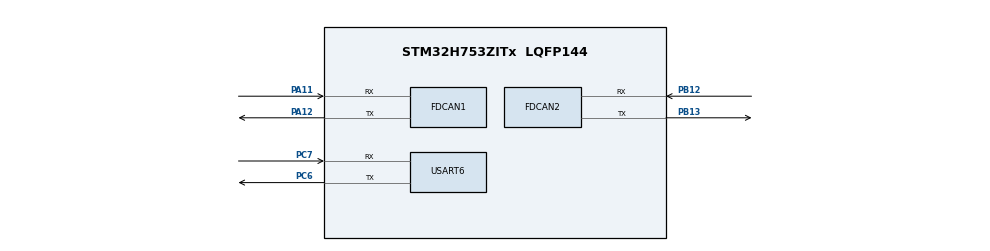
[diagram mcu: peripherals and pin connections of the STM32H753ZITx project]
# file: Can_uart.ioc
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CORTEX_M7.CPU_DCache=Disabled
CORTEX_M7.CPU_ICache=Disabled
CORTEX_M7.MPU_Control=__NULL
CORTEX_M7.default_mode_Activation=1
FDCAN1.CalculateBaudRateNominal=937499
FDCAN1.CalculateTimeBitNominal=1066
FDCAN1.CalculateTimeQuantumNominal=66.66666666666667
FDCAN1.Mode=FDCAN_MODE_INTERNAL_LOOPBACK
FDCAN1.NominalPrescaler=5
FDCAN1.NominalTimeSeg1=13
FDCAN1.NominalTimeSeg2=2
FDCAN1.RxFifo0ElmtsNbr=8
FDCAN1.StdFiltersNbr=64
FDCAN1.TxBuffersNbr=32
FDCAN2.CalculateBaudRateNominal=937499
FDCAN2.CalculateTimeBitNominal=1066
FDCAN2.CalculateTimeQuantumNominal=66.66666666666667
FDCAN2.Mode=FDCAN_MODE_INTERNAL_LOOPBACK
FDCAN2.NominalPrescaler=5
FDCAN2.NominalTimeSeg1=13
FDCAN2.NominalTimeSeg2=2
FDCAN2.RxFifo0ElmtsNbr=8
FDCAN2.StdFiltersNbr=64
FDCAN2.TxBuffersNbr=32
Mcu.Family=STM32H7
Mcu.Name=STM32H753ZITx
Mcu.Package=LQFP144
NVIC.FDCAN1_IT0_IRQn=true\:0\:0\:false\:false\:true\:true\:true\:true
NVIC.FDCAN2_IT0_IRQn=true\:0\:0\:false\:false\:true\:true\:true\:true
NVIC.PriorityGroup=NVIC_PRIORITYGROUP_4
PA11.Mode=FDCAN_Activate
PA11.Signal=FDCAN1_RX
PA12.Mode=FDCAN_Activate
PA12.Signal=FDCAN1_TX
PB0.TagName=LD1
PB12.Mode=FDCAN_Activate
PB12.Signal=FDCAN2_RX
PB13.Mode=FDCAN_Activate
PB13.Signal=FDCAN2_TX
PB14.TagName=LD3
PB7.TagName=LD2
PC13.TagName=BUTTON
PC6.Mode=Asynchronous
PC6.Signal=USART6_TX
PC7.Mode=Asynchronous
PC7.Signal=USART6_RX
PD8.TagName=VCP_TX
PD9.TagName=VCP_RX
ProjectManager.HeapSize=0x200
ProjectManager.StackSize=0x400
ProjectManager.TargetToolchain=STM32CubeIDE
RCC.ADCFreq_Value=129000000
RCC.APB1Freq_Value=64000000
RCC.APB2Freq_Value=64000000
RCC.APB3Freq_Value=64000000
RCC.APB4Freq_Value=64000000
RCC.CortexFreq_Value=64000000
RCC.DIVM1=4
RCC.DIVN1=9
RCC.HCLKFreq_Value=64000000
RCC.HSE_VALUE=8000000
RCC.PLLFRACN=3072
RCC.PWR_Regulator_Voltage_Scale=PWR_REGULATOR_VOLTAGE_SCALE2
RCC.SYSCLKFreq_VALUE=64000000
RCC.USBFreq_Value=75000000
USART6.VirtualMode-Asynchronous=VM_ASYNC
VP_MEMORYMAP_VS_MEMORYMAP.Mode=CurAppReg
board=NUCLEO-H753ZI

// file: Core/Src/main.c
/* USER CODE BEGIN Header */
/**
  ******************************************************************************
  * @file           : main.c
  * @brief          : Main program body
  ******************************************************************************
  * @attention
  *
  * Copyright (c) 2026 STMicroelectronics.
  * All rights reserved.
  *
  * This software is licensed under terms that can be found in the LICENSE file
  * in the root directory of this software component.
  * If no LICENSE file comes with this software, it is provided AS-IS.
  *
  ******************************************************************************
  */
/* USER CODE END Header */

#include "main.h"
#include <stdio.h>
#include <string.h>

FDCAN_HandleTypeDef hfdcan1;
FDCAN_HandleTypeDef hfdcan2;

UART_HandleTypeDef huart6;

/* USER CODE BEGIN PV */
FDCAN_RxHeaderTypeDef RxHeader1;
FDCAN_RxHeaderTypeDef RxHeader2;

uint8_t RxData1[8];
uint8_t RxData2[8];

FDCAN_TxHeaderTypeDef TxHeader;
uint8_t TxData[8];
/* USER CODE END PV */

void SystemClock_Config(void);
static void MX_GPIO_Init(void);
static void MX_FDCAN1_Init(void);
static void MX_FDCAN2_Init(void);
static void MX_USART6_UART_Init(void);

/* USER CODE BEGIN PFP */
void FDCAN_Filter_Config(void);
void FDCAN_Start_All(void);
void Send_CAN(FDCAN_HandleTypeDef *hfdcan, uint32_t id, uint8_t val);
/* USER CODE END PFP */

/* USER CODE BEGIN 0 */

/* printf redirection to UART */
int _write(int file, char *ptr, int len)
{
  HAL_UART_Transmit(&huart6, (uint8_t *)ptr, len, HAL_MAX_DELAY);
  return len;
}

/* Configure Filters + Global Filters */
void FDCAN_Filter_Config(void)
{
  FDCAN_FilterTypeDef sFilter;

  /* ------------ FDCAN1 filter ------------ */
  sFilter.IdType       = FDCAN_STANDARD_ID;
  sFilter.FilterIndex  = 0;
  sFilter.FilterType   = FDCAN_FILTER_MASK;
  sFilter.FilterConfig = FDCAN_FILTER_TO_RXFIFO0;
  sFilter.FilterID1    = 0x111;
  sFilter.FilterID2    = 0x7FF;

  if (HAL_FDCAN_ConfigFilter(&hfdcan1, &sFilter) != HAL_OK)
  {
    Error_Handler();
  }

  /* ------------ FDCAN2 filter ------------ */
  sFilter.FilterIndex  = 0;
  sFilter.FilterID1    = 0x222;

  if (HAL_FDCAN_ConfigFilter(&hfdcan2, &sFilter) != HAL_OK)
  {
    Error_Handler();
  }

  /* Global filter: accept all standard IDs that don't match filters */
  if (HAL_FDCAN_ConfigGlobalFilter(&hfdcan1,
                                  FDCAN_ACCEPT_IN_RX_FIFO0,
                                  FDCAN_ACCEPT_IN_RX_FIFO0,
                                  DISABLE,
                                  DISABLE) != HAL_OK)
  {
    Error_Handler();
  }

  if (HAL_FDCAN_ConfigGlobalFilter(&hfdcan2,
                                  FDCAN_ACCEPT_IN_RX_FIFO0,
                                  FDCAN_ACCEPT_IN_RX_FIFO0,
                                  DISABLE,
                                  DISABLE) != HAL_OK)
  {
    Error_Handler();
  }
}

void FDCAN_Start_All(void)
{
  if (HAL_FDCAN_Start(&hfdcan1) != HAL_OK)
  {
    Error_Handler();
  }

  if (HAL_FDCAN_Start(&hfdcan2) != HAL_OK)
  {
    Error_Handler();
  }

  if (HAL_FDCAN_ActivateNotification(&hfdcan1, FDCAN_IT_RX_FIFO0_NEW_MESSAGE, 0) != HAL_OK)
  {
    Error_Handler();
  }

  if (HAL_FDCAN_ActivateNotification(&hfdcan2, FDCAN_IT_RX_FIFO0_NEW_MESSAGE, 0) != HAL_OK)
  {
    Error_Handler();
  }
}

void Send_CAN(FDCAN_HandleTypeDef *hfdcan, uint32_t id, uint8_t val)
{
  TxHeader.Identifier          = id;
  TxHeader.IdType              = FDCAN_STANDARD_ID;
  TxHeader.TxFrameType         = FDCAN_DATA_FRAME;
  TxHeader.DataLength          = FDCAN_DLC_BYTES_1;
  TxHeader.ErrorStateIndicator = FDCAN_ESI_ACTIVE;
  TxHeader.BitRateSwitch       = FDCAN_BRS_OFF;
  TxHeader.FDFormat            = FDCAN_CLASSIC_CAN;
  TxHeader.TxEventFifoControl  = FDCAN_NO_TX_EVENTS;
  TxHeader.MessageMarker       = 0;

  TxData[0] = val;

  if (HAL_FDCAN_AddMessageToTxFifoQ(hfdcan, &TxHeader, TxData) != HAL_OK)
  {
    Error_Handler();
  }
}

/* RX Callback */
void HAL_FDCAN_RxFifo0Callback(FDCAN_HandleTypeDef *hfdcan, uint32_t RxFifo0ITs)
{
  if ((RxFifo0ITs & FDCAN_IT_RX_FIFO0_NEW_MESSAGE) != 0U)
  {
    if (hfdcan->Instance == FDCAN1)
    {
      HAL_FDCAN_GetRxMessage(hfdcan, FDCAN_RX_FIFO0, &RxHeader1, RxData1);
      printf("Received data CAN1_TX On CAN_2RX Successfully : Data=%d\r\n", RxData1[0]);
    }
    else if (hfdcan->Instance == FDCAN2)
    {
      HAL_FDCAN_GetRxMessage(hfdcan, FDCAN_RX_FIFO0, &RxHeader2, RxData2);
      printf("Received data CAN2_TX On CAN_1RX Successfully : Data=%d\r\n", RxData2[0]);
    }
  }
}

/* USER CODE END 0 */

int main(void)
{
  HAL_Init();
  SystemClock_Config();

  MX_GPIO_Init();
  MX_FDCAN1_Init();
  MX_FDCAN2_Init();
  MX_USART6_UART_Init();

  /* USER CODE BEGIN 2 */
  printf("\r\n==============================\r\n");
  printf("CAN Dual Controller Test Started...\r\n");
  printf("==============================\r\n");

  FDCAN_Filter_Config();
  FDCAN_Start_All();

  HAL_Delay(500);

  /* 1) CAN1TX -> CAN2RX (3 times) */
  for (int i = 1; i <= 3; i++)
  {
    printf("Sending CAN1TX -> CAN2RX : %d\r\n", i);
    Send_CAN(&hfdcan1, 0x111, i);
    HAL_Delay(500);
  }

  /* 2) CAN2TX -> CAN1RX (3 times) */
  for (int i = 1; i <= 3; i++)
  {
    printf("Sending CAN2TX -> CAN1RX : %d\r\n", i);
    Send_CAN(&hfdcan2, 0x222, i);
    HAL_Delay(500);
  }

  printf("Completed ✅\r\n");
  /* USER CODE END 2 */

  while (1)
  {
  }
}

void SystemClock_Config(void)
{
  RCC_OscInitTypeDef RCC_OscInitStruct = {0};
  RCC_ClkInitTypeDef RCC_ClkInitStruct = {0};

  HAL_PWREx_ConfigSupply(PWR_LDO_SUPPLY);
  __HAL_PWR_VOLTAGESCALING_CONFIG(PWR_REGULATOR_VOLTAGE_SCALE3);

  while (!__HAL_PWR_GET_FLAG(PWR_FLAG_VOSRDY)) {}

  RCC_OscInitStruct.OscillatorType = RCC_OSCILLATORTYPE_HSI;
  RCC_OscInitStruct.HSIState = RCC_HSI_DIV1;
  RCC_OscInitStruct.HSICalibrationValue = RCC_HSICALIBRATION_DEFAULT;
  RCC_OscInitStruct.PLL.PLLState = RCC_PLL_ON;
  RCC_OscInitStruct.PLL.PLLSource = RCC_PLLSOURCE_HSI;
  RCC_OscInitStruct.PLL.PLLM = 4;
  RCC_OscInitStruct.PLL.PLLN = 9;
  RCC_OscInitStruct.PLL.PLLP = 2;
  RCC_OscInitStruct.PLL.PLLQ = 3;
  RCC_OscInitStruct.PLL.PLLR = 2;
  RCC_OscInitStruct.PLL.PLLRGE = RCC_PLL1VCIRANGE_3;
  RCC_OscInitStruct.PLL.PLLVCOSEL = RCC_PLL1VCOMEDIUM;
  RCC_OscInitStruct.PLL.PLLFRACN = 3072;

  if (HAL_RCC_OscConfig(&RCC_OscInitStruct) != HAL_OK)
  {
    Error_Handler();
  }

  RCC_ClkInitStruct.ClockType = RCC_CLOCKTYPE_HCLK | RCC_CLOCKTYPE_SYSCLK
                              | RCC_CLOCKTYPE_PCLK1 | RCC_CLOCKTYPE_PCLK2
                              | RCC_CLOCKTYPE_D3PCLK1 | RCC_CLOCKTYPE_D1PCLK1;

  RCC_ClkInitStruct.SYSCLKSource = RCC_SYSCLKSOURCE_HSI;
  RCC_ClkInitStruct.SYSCLKDivider = RCC_SYSCLK_DIV1;
  RCC_ClkInitStruct.AHBCLKDivider = RCC_HCLK_DIV1;
  RCC_ClkInitStruct.APB3CLKDivider = RCC_APB3_DIV1;
  RCC_ClkInitStruct.APB1CLKDivider = RCC_APB1_DIV1;
  RCC_ClkInitStruct.APB2CLKDivider = RCC_APB2_DIV2;
  RCC_ClkInitStruct.APB4CLKDivider = RCC_APB4_DIV1;

  if (HAL_RCC_ClockConfig(&RCC_ClkInitStruct, FLASH_LATENCY_1) != HAL_OK)
  {
    Error_Handler();
  }
}

static void MX_FDCAN1_Init(void)
{
  hfdcan1.Instance = FDCAN1;

  hfdcan1.Init.FrameFormat = FDCAN_FRAME_CLASSIC;

  /* KEY FIX: Internal Loopback for NO Transceiver */
  hfdcan1.Init.Mode = FDCAN_MODE_INTERNAL_LOOPBACK;

  hfdcan1.Init.AutoRetransmission = DISABLE;
  hfdcan1.Init.TransmitPause = DISABLE;
  hfdcan1.Init.ProtocolException = DISABLE;

  hfdcan1.Init.NominalPrescaler = 5;
  hfdcan1.Init.NominalSyncJumpWidth = 1;
  hfdcan1.Init.NominalTimeSeg1 = 13;
  hfdcan1.Init.NominalTimeSeg2 = 2;

  hfdcan1.Init.DataPrescaler = 1;
  hfdcan1.Init.DataSyncJumpWidth = 1;
  hfdcan1.Init.DataTimeSeg1 = 1;
  hfdcan1.Init.DataTimeSeg2 = 1;

  hfdcan1.Init.MessageRAMOffset = 0;
  hfdcan1.Init.StdFiltersNbr = 64;
  hfdcan1.Init.ExtFiltersNbr = 0;

  hfdcan1.Init.RxFifo0ElmtsNbr = 8;
  hfdcan1.Init.RxFifo0ElmtSize = FDCAN_DATA_BYTES_8;

  hfdcan1.Init.RxFifo1ElmtsNbr = 0;
  hfdcan1.Init.RxFifo1ElmtSize = FDCAN_DATA_BYTES_8;

  hfdcan1.Init.RxBuffersNbr = 0;
  hfdcan1.Init.RxBufferSize = FDCAN_DATA_BYTES_8;

  hfdcan1.Init.TxEventsNbr = 0;
  hfdcan1.Init.TxBuffersNbr = 0;
  hfdcan1.Init.TxFifoQueueElmtsNbr = 8;
  hfdcan1.Init.TxFifoQueueMode = FDCAN_TX_FIFO_OPERATION;
  hfdcan1.Init.TxElmtSize = FDCAN_DATA_BYTES_8;

  if (HAL_FDCAN_Init(&hfdcan1) != HAL_OK)
  {
    Error_Handler();
  }
}

static void MX_FDCAN2_Init(void)
{
  hfdcan2.Instance = FDCAN2;

  hfdcan2.Init.FrameFormat = FDCAN_FRAME_CLASSIC;

  /* KEY FIX: Internal Loopback for NO Transceiver */
  hfdcan2.Init.Mode = FDCAN_MODE_INTERNAL_LOOPBACK;

  hfdcan2.Init.AutoRetransmission = DISABLE;
  hfdcan2.Init.TransmitPause = DISABLE;
  hfdcan2.Init.ProtocolException = DISABLE;

  hfdcan2.Init.NominalPrescaler = 5;
  hfdcan2.Init.NominalSyncJumpWidth = 1;
  hfdcan2.Init.NominalTimeSeg1 = 13;
  hfdcan2.Init.NominalTimeSeg2 = 2;

  hfdcan2.Init.DataPrescaler = 1;
  hfdcan2.Init.DataSyncJumpWidth = 1;
  hfdcan2.Init.DataTimeSeg1 = 1;
  hfdcan2.Init.DataTimeSeg2 = 1;

  hfdcan2.Init.MessageRAMOffset = 256;
  hfdcan2.Init.StdFiltersNbr = 64;
  hfdcan2.Init.ExtFiltersNbr = 0;

  hfdcan2.Init.RxFifo0ElmtsNbr = 8;
  hfdcan2.Init.RxFifo0ElmtSize = FDCAN_DATA_BYTES_8;

  hfdcan2.Init.RxFifo1ElmtsNbr = 0;
  hfdcan2.Init.RxFifo1ElmtSize = FDCAN_DATA_BYTES_8;

  hfdcan2.Init.RxBuffersNbr = 0;
  hfdcan2.Init.RxBufferSize = FDCAN_DATA_BYTES_8;

  hfdcan2.Init.TxEventsNbr = 0;
  hfdcan2.Init.TxBuffersNbr = 0;
  hfdcan2.Init.TxFifoQueueElmtsNbr = 8;
  hfdcan2.Init.TxFifoQueueMode = FDCAN_TX_FIFO_OPERATION;
  hfdcan2.Init.TxElmtSize = FDCAN_DATA_BYTES_8;

  if (HAL_FDCAN_Init(&hfdcan2) != HAL_OK)
  {
    Error_Handler();
  }
}

static void MX_USART6_UART_Init(void)
{
  huart6.Instance = USART6;
  huart6.Init.BaudRate = 115200;
  huart6.Init.WordLength = UART_WORDLENGTH_8B;
  huart6.Init.StopBits = UART_STOPBITS_1;
  huart6.Init.Parity = UART_PARITY_NONE;
  huart6.Init.Mode = UART_MODE_TX_RX;
  huart6.Init.HwFlowCtl = UART_HWCONTROL_NONE;
  huart6.Init.OverSampling = UART_OVERSAMPLING_16;
  huart6.Init.OneBitSampling = UART_ONE_BIT_SAMPLE_DISABLE;
  huart6.Init.ClockPrescaler = UART_PRESCALER_DIV1;
  huart6.AdvancedInit.AdvFeatureInit = UART_ADVFEATURE_NO_INIT;

  if (HAL_UART_Init(&huart6) != HAL_OK)
  {
    Error_Handler();
  }

  if (HAL_UARTEx_SetTxFifoThreshold(&huart6, UART_TXFIFO_THRESHOLD_1_8) != HAL_OK)
  {
    Error_Handler();
  }

  if (HAL_UARTEx_SetRxFifoThreshold(&huart6, UART_RXFIFO_THRESHOLD_1_8) != HAL_OK)
  {
    Error_Handler();
  }

  if (HAL_UARTEx_DisableFifoMode(&huart6) != HAL_OK)
  {
    Error_Handler();
  }
}

static void MX_GPIO_Init(void)
{
  __HAL_RCC_GPIOB_CLK_ENABLE();
  __HAL_RCC_GPIOC_CLK_ENABLE();
  __HAL_RCC_GPIOA_CLK_ENABLE();
}

void Error_Handler(void)
{
  __disable_irq();
  while (1)
  {
  }
}
